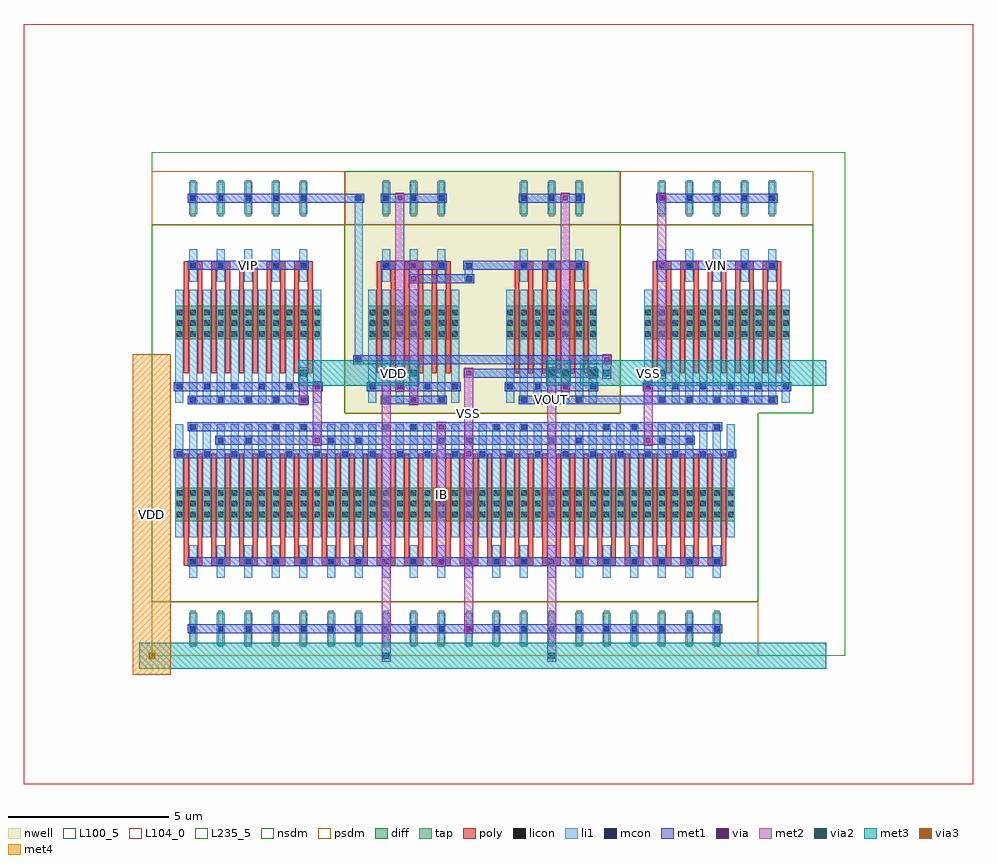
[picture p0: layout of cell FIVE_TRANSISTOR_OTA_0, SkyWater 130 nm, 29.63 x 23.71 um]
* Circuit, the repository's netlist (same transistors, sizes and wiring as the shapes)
* NGSPICE file created from FIVE_TRANSISTOR_OTA_0.ext - technology: sky130A

.subckt PMOS_S_55262173_X3_Y1_1774869087 a_230_462# a_200_252# w_0_0#
X0 w_0_0# a_200_252# a_230_462# w_0_0# sky130_fd_pr__pfet_01v8 ad=0.147 pd=1.33 as=0.147 ps=1.33 w=1.05 l=0.15 M=6
.ends

.subckt SCM_NMOS_33182518_X10_Y1_1774869088 a_200_252# a_402_462# a_147_462#
X0 a_402_462# a_200_252# a_147_462# a_147_462# sky130_fd_pr__nfet_01v8 ad=0.147 pd=1.33 as=0.147 ps=1.33 w=1.05 l=0.15 M=20
X1 a_147_462# a_200_252# a_200_252# a_147_462# sky130_fd_pr__nfet_01v8 ad=0.27825 pd=2.63 as=0.147 ps=1.33 w=1.05 l=0.15 M=20
.ends

.subckt DCL_PMOS_S_56391010_X3_Y1_1774869085 a_200_252# w_0_0#
X0 w_0_0# a_200_252# a_200_252# w_0_0# sky130_fd_pr__pfet_01v8 ad=0.147 pd=1.33 as=0.147 ps=1.33 w=1.05 l=0.15 M=6
.ends

.subckt NMOS_4T_70086367_X5_Y1_1774869086 a_230_462# a_200_252# a_147_462# a_241_1232#
X0 a_230_462# a_200_252# a_147_462# a_241_1232# sky130_fd_pr__nfet_01v8 ad=0.147 pd=1.33 as=0.147 ps=1.33 w=1.05 l=0.15 M=10
.ends

.subckt FIVE_TRANSISTOR_OTA_0 IB VOUT VIP VIN VSS VDD
XPMOS_S_55262173_X3_Y1_1774869087_0 VOUT m1_914_1568# VDD PMOS_S_55262173_X3_Y1_1774869087
XSCM_NMOS_33182518_X10_Y1_1774869088_0 IB m1_3064_1316# VSS SCM_NMOS_33182518_X10_Y1_1774869088
XDCL_PMOS_S_56391010_X3_Y1_1774869085_0 m1_914_1568# VDD DCL_PMOS_S_56391010_X3_Y1_1774869085
XNMOS_4T_70086367_X5_Y1_1774869086_0 VOUT VIN m1_3064_1316# VSS NMOS_4T_70086367_X5_Y1_1774869086
XNMOS_4T_70086367_X5_Y1_1774869086_1 m1_914_1568# VIP m1_3064_1316# VSS NMOS_4T_70086367_X5_Y1_1774869086
.ends

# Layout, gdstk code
from math import pi, radians
import gdstk
lib = gdstk.Library(unit=1e-6, precision=1e-09)
def R(c, l, rs):  # rectangles x0, y0, x1, y1
    for r in rs: c.add(gdstk.rectangle(r[:2], r[2:], *l))
def A(c, l, x, y, w, h, nx, ny, dx, dy):  # array of equal rectangles
    R(c, l, [(x+i*dx, y+j*dy, x+i*dx+w, y+j*dy+h) for i in range(nx) for j in range(ny)])
def P(c, l, *ps):  # polygons
    for p in ps: c.add(gdstk.Polygon(p, *l))
nwell = (64, 20)
diff = (65, 20)
tap = (65, 44)
poly = (66, 20)
licon = (66, 44)
li1 = (67, 20)
mcon = (67, 44)
met1 = (68, 20)
via = (68, 44)
met2 = (69, 20)
via2 = (69, 44)
met3 = (70, 20)
via3 = (70, 44)
met4 = (71, 20)
nsdm = (93, 44)
psdm = (94, 20)
L100_5 = (100, 5)
L104_0 = (104, 0)
L235_5 = (235, 5)

scm_nmos_33182518_x10_y1 = lib.new_cell('SCM_NMOS_33182518_X10_Y1_1774869088')
R(scm_nmos_33182518_x10_y1, diff, [(0.735,2.31,18.185,3.36)])
A(scm_nmos_33182518_x10_y1, tap, 1.205, 6.16, 0.17, 1.12, 20, 1, 0.86, 0)
A(scm_nmos_33182518_x10_y1, poly, 1, 1.26, 0.15, 3.36, 40, 1, 0.43, 0)
A(scm_nmos_33182518_x10_y1, poly, 1, 4.485, 0.58, 0.27, 20, 1, 0.86, 0)
A(scm_nmos_33182518_x10_y1, licon, 0.775, 2.39, 0.17, 0.17, 3, 3, 0.43, 0.34)
A(scm_nmos_33182518_x10_y1, licon, 1.635, 2.39, 0.17, 0.17, 3, 3, 0.43, 0.34)
A(scm_nmos_33182518_x10_y1, licon, 2.495, 2.39, 0.17, 0.17, 3, 3, 0.43, 0.34)
A(scm_nmos_33182518_x10_y1, licon, 3.355, 2.39, 0.17, 0.17, 3, 3, 0.43, 0.34)
A(scm_nmos_33182518_x10_y1, licon, 4.215, 2.39, 0.17, 0.17, 3, 3, 0.43, 0.34)
A(scm_nmos_33182518_x10_y1, licon, 5.075, 2.39, 0.17, 0.17, 3, 3, 0.43, 0.34)
A(scm_nmos_33182518_x10_y1, licon, 5.935, 2.39, 0.17, 0.17, 3, 3, 0.43, 0.34)
A(scm_nmos_33182518_x10_y1, licon, 6.795, 2.39, 0.17, 0.17, 3, 3, 0.43, 0.34)
A(scm_nmos_33182518_x10_y1, licon, 7.655, 2.39, 0.17, 0.17, 3, 3, 0.43, 0.34)
A(scm_nmos_33182518_x10_y1, licon, 8.515, 2.39, 0.17, 0.17, 3, 3, 0.43, 0.34)
A(scm_nmos_33182518_x10_y1, licon, 9.375, 2.39, 0.17, 0.17, 3, 3, 0.43, 0.34)
A(scm_nmos_33182518_x10_y1, licon, 10.235, 2.39, 0.17, 0.17, 3, 3, 0.43, 0.34)
A(scm_nmos_33182518_x10_y1, licon, 11.095, 2.39, 0.17, 0.17, 3, 3, 0.43, 0.34)
A(scm_nmos_33182518_x10_y1, licon, 11.955, 2.39, 0.17, 0.17, 3, 3, 0.43, 0.34)
A(scm_nmos_33182518_x10_y1, licon, 12.815, 2.39, 0.17, 0.17, 3, 3, 0.43, 0.34)
A(scm_nmos_33182518_x10_y1, licon, 13.675, 2.39, 0.17, 0.17, 3, 3, 0.43, 0.34)
A(scm_nmos_33182518_x10_y1, licon, 14.535, 2.39, 0.17, 0.17, 3, 3, 0.43, 0.34)
A(scm_nmos_33182518_x10_y1, licon, 15.395, 2.39, 0.17, 0.17, 3, 3, 0.43, 0.34)
A(scm_nmos_33182518_x10_y1, licon, 16.255, 2.39, 0.17, 0.17, 3, 3, 0.43, 0.34)
A(scm_nmos_33182518_x10_y1, licon, 17.115, 2.39, 0.17, 0.17, 3, 3, 0.43, 0.34)
A(scm_nmos_33182518_x10_y1, licon, 1.205, 4.535, 0.17, 0.17, 20, 2, 0.86, 2.1)
A(scm_nmos_33182518_x10_y1, li1, 0.735, 0.335, 0.25, 3.53, 41, 1, 0.43, 0)
A(scm_nmos_33182518_x10_y1, li1, 1.165, 4.115, 0.25, 1.01, 20, 2, 0.86, 2.1)
A(scm_nmos_33182518_x10_y1, mcon, 0.775, 1.175, 0.17, 0.17, 21, 1, 0.86, 0)
A(scm_nmos_33182518_x10_y1, mcon, 1.205, 4.535, 0.17, 0.17, 20, 2, 0.86, 2.1)
R(scm_nmos_33182518_x10_y1, mcon, [(1.205,0.335,1.375,0.505), (3.785,0.335,3.955,0.505), (4.645,0.335,4.815,0.505), (7.225,0.335,7.395,0.505), (8.085,0.335,8.255,0.505), (10.665,0.335,10.835,0.505), (11.525,0.335,11.695,0.505), (14.105,0.335,14.275,0.505), (14.965,0.335,15.135,0.505), (17.545,0.335,17.715,0.505), (2.065,0.755,2.235,0.925), (2.925,0.755,3.095,0.925), (5.505,0.755,5.675,0.925), (6.365,0.755,6.535,0.925), (8.945,0.755,9.115,0.925), (9.805,0.755,9.975,0.925), (12.385,0.755,12.555,0.925), (13.245,0.755,13.415,0.925), (15.825,0.755,15.995,0.925), (16.685,0.755,16.855,0.925)])
R(scm_nmos_33182518_x10_y1, met1, [(1.12,0.28,17.8,0.56), (1.98,0.7,16.94,0.98), (0.69,1.12,18.23,1.4), (1.12,4.48,17.8,4.76), (1.12,6.58,17.8,6.86)])
R(scm_nmos_33182518_x10_y1, via, [(8.955,0.345,9.105,0.495), (9.815,1.185,9.965,1.335), (8.955,4.545,9.105,4.695), (9.815,6.645,9.965,6.795)])
R(scm_nmos_33182518_x10_y1, met2, [(8.89,0.26,9.17,4.78), (9.75,1.1,10.03,6.88)])
R(scm_nmos_33182518_x10_y1, nsdm, [(0,0,18.92,5.88)])
R(scm_nmos_33182518_x10_y1, psdm, [(0,5.88,18.92,7.56)])
R(scm_nmos_33182518_x10_y1, L100_5, [(0,0,18.92,7.56)])

dcl_pmos_s_56391010_x3_y = lib.new_cell('DCL_PMOS_S_56391010_X3_Y1_1774869085')
R(dcl_pmos_s_56391010_x3_y, nwell, [(0,0,4.3,7.56)])
R(dcl_pmos_s_56391010_x3_y, diff, [(0.735,2.31,3.565,3.36)])
A(dcl_pmos_s_56391010_x3_y, tap, 1.205, 6.16, 0.17, 1.12, 3, 1, 0.86, 0)
A(dcl_pmos_s_56391010_x3_y, poly, 1, 1.26, 0.15, 3.36, 6, 1, 0.43, 0)
A(dcl_pmos_s_56391010_x3_y, poly, 1, 4.485, 0.58, 0.27, 3, 1, 0.86, 0)
A(dcl_pmos_s_56391010_x3_y, licon, 0.775, 2.39, 0.17, 0.17, 3, 3, 0.43, 0.34)
A(dcl_pmos_s_56391010_x3_y, licon, 1.635, 2.39, 0.17, 0.17, 3, 3, 0.43, 0.34)
A(dcl_pmos_s_56391010_x3_y, licon, 2.495, 2.39, 0.17, 0.17, 3, 3, 0.43, 0.34)
A(dcl_pmos_s_56391010_x3_y, licon, 1.205, 4.535, 0.17, 0.17, 3, 2, 0.86, 2.1)
A(dcl_pmos_s_56391010_x3_y, li1, 0.735, 0.335, 0.25, 3.53, 7, 1, 0.43, 0)
A(dcl_pmos_s_56391010_x3_y, li1, 1.165, 4.115, 0.25, 1.01, 3, 2, 0.86, 2.1)
A(dcl_pmos_s_56391010_x3_y, mcon, 1.205, 0.335, 0.17, 0.17, 3, 2, 0.86, 4.2)
A(dcl_pmos_s_56391010_x3_y, mcon, 0.775, 0.755, 0.17, 0.17, 4, 1, 0.86, 0)
A(dcl_pmos_s_56391010_x3_y, mcon, 1.205, 6.635, 0.17, 0.17, 3, 1, 0.86, 0)
R(dcl_pmos_s_56391010_x3_y, met1, [(1.12,0.28,3.18,0.56), (0.69,0.7,3.61,0.98), (1.12,4.48,3.18,4.76), (1.12,6.58,3.18,6.86)])
R(dcl_pmos_s_56391010_x3_y, via, [(2.075,0.345,2.225,0.495), (2.505,0.765,2.655,0.915), (2.075,4.545,2.225,4.695), (2.505,6.645,2.655,6.795)])
R(dcl_pmos_s_56391010_x3_y, met2, [(2.01,0.26,2.29,4.78), (2.44,0.68,2.72,6.88)])
R(dcl_pmos_s_56391010_x3_y, nsdm, [(0,5.88,4.3,7.56)])
R(dcl_pmos_s_56391010_x3_y, psdm, [(0,0,4.3,5.88)])
R(dcl_pmos_s_56391010_x3_y, L100_5, [(0,0,4.3,7.56)])

pmos_s_55262173_x3_y1_17 = lib.new_cell('PMOS_S_55262173_X3_Y1_1774869087')
R(pmos_s_55262173_x3_y1_17, nwell, [(0,0,4.3,7.56)])
R(pmos_s_55262173_x3_y1_17, diff, [(0.735,2.31,3.565,3.36)])
A(pmos_s_55262173_x3_y1_17, tap, 1.205, 6.16, 0.17, 1.12, 3, 1, 0.86, 0)
A(pmos_s_55262173_x3_y1_17, poly, 1, 1.26, 0.15, 3.36, 6, 1, 0.43, 0)
A(pmos_s_55262173_x3_y1_17, poly, 1, 4.485, 0.58, 0.27, 3, 1, 0.86, 0)
A(pmos_s_55262173_x3_y1_17, licon, 0.775, 2.39, 0.17, 0.17, 3, 3, 0.43, 0.34)
A(pmos_s_55262173_x3_y1_17, licon, 1.635, 2.39, 0.17, 0.17, 3, 3, 0.43, 0.34)
A(pmos_s_55262173_x3_y1_17, licon, 2.495, 2.39, 0.17, 0.17, 3, 3, 0.43, 0.34)
A(pmos_s_55262173_x3_y1_17, licon, 1.205, 4.535, 0.17, 0.17, 3, 2, 0.86, 2.1)
A(pmos_s_55262173_x3_y1_17, li1, 0.735, 0.335, 0.25, 3.53, 7, 1, 0.43, 0)
A(pmos_s_55262173_x3_y1_17, li1, 1.165, 4.115, 0.25, 1.01, 3, 2, 0.86, 2.1)
A(pmos_s_55262173_x3_y1_17, mcon, 1.205, 0.335, 0.17, 0.17, 3, 2, 0.86, 4.2)
A(pmos_s_55262173_x3_y1_17, mcon, 0.775, 0.755, 0.17, 0.17, 4, 1, 0.86, 0)
A(pmos_s_55262173_x3_y1_17, mcon, 1.205, 6.635, 0.17, 0.17, 3, 1, 0.86, 0)
R(pmos_s_55262173_x3_y1_17, met1, [(1.12,0.28,3.18,0.56), (0.69,0.7,3.61,0.98), (1.12,4.48,3.18,4.76), (1.12,6.58,3.18,6.86)])
R(pmos_s_55262173_x3_y1_17, via, [(2.505,0.765,2.655,0.915), (2.505,6.645,2.655,6.795)])
R(pmos_s_55262173_x3_y1_17, met2, [(2.44,0.68,2.72,6.88)])
R(pmos_s_55262173_x3_y1_17, nsdm, [(0,5.88,4.3,7.56)])
R(pmos_s_55262173_x3_y1_17, psdm, [(0,0,4.3,5.88)])
R(pmos_s_55262173_x3_y1_17, L100_5, [(0,0,4.3,7.56)])

nmos_4t_70086367_x5_y1_1 = lib.new_cell('NMOS_4T_70086367_X5_Y1_1774869086')
R(nmos_4t_70086367_x5_y1_1, diff, [(0.735,2.31,5.285,3.36)])
A(nmos_4t_70086367_x5_y1_1, tap, 1.205, 6.16, 0.17, 1.12, 5, 1, 0.86, 0)
A(nmos_4t_70086367_x5_y1_1, poly, 1, 1.26, 0.15, 3.36, 10, 1, 0.43, 0)
A(nmos_4t_70086367_x5_y1_1, poly, 1, 4.485, 0.58, 0.27, 5, 1, 0.86, 0)
A(nmos_4t_70086367_x5_y1_1, licon, 0.775, 2.39, 0.17, 0.17, 3, 3, 0.43, 0.34)
A(nmos_4t_70086367_x5_y1_1, licon, 1.635, 2.39, 0.17, 0.17, 3, 3, 0.43, 0.34)
A(nmos_4t_70086367_x5_y1_1, licon, 2.495, 2.39, 0.17, 0.17, 3, 3, 0.43, 0.34)
A(nmos_4t_70086367_x5_y1_1, licon, 3.355, 2.39, 0.17, 0.17, 3, 3, 0.43, 0.34)
A(nmos_4t_70086367_x5_y1_1, licon, 4.215, 2.39, 0.17, 0.17, 3, 3, 0.43, 0.34)
A(nmos_4t_70086367_x5_y1_1, licon, 1.205, 4.535, 0.17, 0.17, 5, 2, 0.86, 2.1)
A(nmos_4t_70086367_x5_y1_1, li1, 0.735, 0.335, 0.25, 3.53, 11, 1, 0.43, 0)
A(nmos_4t_70086367_x5_y1_1, li1, 1.165, 4.115, 0.25, 1.01, 5, 2, 0.86, 2.1)
A(nmos_4t_70086367_x5_y1_1, mcon, 1.205, 0.335, 0.17, 0.17, 5, 2, 0.86, 4.2)
A(nmos_4t_70086367_x5_y1_1, mcon, 0.775, 0.755, 0.17, 0.17, 6, 1, 0.86, 0)
A(nmos_4t_70086367_x5_y1_1, mcon, 1.205, 6.635, 0.17, 0.17, 5, 1, 0.86, 0)
R(nmos_4t_70086367_x5_y1_1, met1, [(1.12,0.28,4.9,0.56), (0.69,0.7,5.33,0.98), (1.12,4.48,4.9,4.76), (1.12,6.58,4.9,6.86)])
R(nmos_4t_70086367_x5_y1_1, nsdm, [(0,0,6.02,5.88)])
R(nmos_4t_70086367_x5_y1_1, psdm, [(0,5.88,6.02,7.56)])
R(nmos_4t_70086367_x5_y1_1, L100_5, [(0,0,6.02,7.56)])

five_transistor_ota_0 = lib.new_cell('FIVE_TRANSISTOR_OTA_0')
R(five_transistor_ota_0, li1, [(6.325,9.155,6.575,9.325), (6.325,9.155,6.575,9.325), (6.325,9.155,6.575,9.325), (6.325,9.24,6.575,14.28), (9.765,11.675,10.015,11.845), (9.765,11.675,10.015,11.845), (9.765,11.76,10.015,12.18), (9.765,12.095,10.015,12.265), (9.765,12.095,10.015,12.265), (6.325,14.195,6.575,14.365), (6.325,14.195,6.575,14.365), (6.325,14.195,6.575,14.365)])
R(five_transistor_ota_0, mcon, [(6.365,9.155,6.535,9.325), (6.365,9.155,6.535,9.325), (6.365,9.155,6.535,9.325), (9.805,11.675,9.975,11.845), (9.805,11.675,9.975,11.845), (9.805,12.095,9.975,12.265), (9.805,12.095,9.975,12.265), (6.365,14.195,6.535,14.365), (6.365,14.195,6.535,14.365), (6.365,14.195,6.535,14.365)])
R(five_transistor_ota_0, met1, [(5,6.58,5.32,6.86), (5,6.58,5.32,6.86), (5,6.58,5.32,6.86), (5,6.58,5.32,6.86), (15.32,6.58,15.64,6.86), (15.32,6.58,15.64,6.86), (4.57,7.84,4.89,8.12), (4.57,7.84,4.89,8.12), (4.57,7.84,4.89,8.12), (4.57,7.84,4.89,8.12), (13.33,7.84,15.91,8.12), (5,8.26,5.32,8.54), (5,8.26,5.32,8.54), (5,8.26,5.32,8.54), (5,8.26,5.32,8.54), (15.32,8.26,15.64,8.54), (15.32,8.26,15.64,8.54), (7.15,8.68,7.47,8.96), (7.15,8.68,7.47,8.96), (7.15,8.68,7.47,8.96), (7.31,8.68,7.74,8.96), (7.58,8.68,7.9,8.96), (7.58,8.68,7.9,8.96), (7.58,8.68,7.9,8.96), (9.73,8.68,10.05,8.96), (9.73,8.68,10.05,8.96), (9.73,8.68,10.05,8.96), (9.73,8.68,10.05,8.96), (9.89,8.68,13.76,8.96), (13.6,8.68,13.92,8.96), (6.28,9.1,6.62,9.38), (6.28,9.1,6.62,9.38), (6.28,9.1,6.62,9.38), (6.45,9.1,14.19,9.38), (14.03,9.1,14.35,9.38), (14.03,9.1,14.35,9.38), (14.03,9.1,14.35,9.38), (8.01,11.62,8.33,11.9), (8.01,11.62,8.33,11.9), (8.17,11.62,9.89,11.9), (9.72,11.62,10.06,11.9), (9.72,11.62,10.06,11.9), (9.72,12.04,10.06,12.32), (9.72,12.04,10.06,12.32), (9.89,12.04,11.61,12.32), (4.73,14.14,6.45,14.42), (6.28,14.14,6.62,14.42), (6.28,14.14,6.62,14.42), (6.28,14.14,6.62,14.42), (15.75,14.14,16.07,14.42), (15.75,14.14,16.07,14.42)])
P(five_transistor_ota_0, met1, [(0,0),(0,0),(0,0),(0,0)],
  [(0,0),(0,0),(0,0),(0,0)],
  [(0,0),(0,0),(0,0),(0,0)],
  [(0,0),(0,0),(0,0),(0,0)],
  [(0,0),(0,0),(0,0),(0,0)],
  [(0,0),(0,0),(0,0),(0,0)],
  [(0,0),(0,0),(0,0),(0,0)],
  [(0,0),(0,0),(0,0),(0,0)],
  [(0,0),(0,0),(0,0),(0,0)],
  [(0,0),(0,0),(0,0),(0,0)],
  [(0,0),(0,0),(0,0),(0,0)],
  [(0,0),(0,0),(0,0),(0,0)],
  [(0,0),(0,0),(0,0),(0,0)],
  [(0,0),(0,0),(0,0),(0,0)])
R(five_transistor_ota_0, via, [(5.085,6.645,5.235,6.795), (5.085,6.645,5.235,6.795), (5.085,6.645,5.235,6.795), (5.085,6.645,5.235,6.795), (15.405,6.645,15.555,6.795), (15.405,6.645,15.555,6.795), (4.655,7.905,4.805,8.055), (4.655,7.905,4.805,8.055), (4.655,7.905,4.805,8.055), (4.655,7.905,4.805,8.055), (5.085,8.325,5.235,8.475), (5.085,8.325,5.235,8.475), (5.085,8.325,5.235,8.475), (5.085,8.325,5.235,8.475), (15.405,8.325,15.555,8.475), (15.405,8.325,15.555,8.475), (7.235,8.745,7.385,8.895), (7.235,8.745,7.385,8.895), (7.235,8.745,7.385,8.895), (7.665,8.745,7.815,8.895), (7.665,8.745,7.815,8.895), (7.665,8.745,7.815,8.895), (9.815,8.745,9.965,8.895), (9.815,8.745,9.965,8.895), (9.815,8.745,9.965,8.895), (9.815,8.745,9.965,8.895), (13.685,8.745,13.835,8.895), (14.115,9.165,14.265,9.315), (14.115,9.165,14.265,9.315), (14.115,9.165,14.265,9.315), (8.095,11.685,8.245,11.835), (8.095,11.685,8.245,11.835), (15.835,14.205,15.985,14.355), (15.835,14.205,15.985,14.355)])
R(five_transistor_ota_0, met2, [(7.17,-0.185,7.45,0.185), (7.17,-0.185,7.45,0.185), (7.17,-0.185,7.45,0.185), (12.33,-0.185,12.61,0.185), (12.33,-0.185,12.61,0.185), (7.17,0,7.45,8.82), (12.33,0,12.61,8.82), (9.75,6.3,10.03,8.82), (5.02,6.56,5.3,6.88), (5.02,6.56,5.3,6.88), (5.02,6.56,5.3,6.88), (5.02,6.56,5.3,6.88), (15.34,6.56,15.62,6.88), (15.34,6.56,15.62,6.88), (5.02,6.72,5.3,8.4), (15.34,6.72,15.62,8.4), (4.59,7.82,4.87,8.14), (4.59,7.82,4.87,8.14), (4.59,7.82,4.87,8.14), (4.59,7.82,4.87,8.14), (4.59,7.98,4.87,8.82), (5.02,8.24,5.3,8.56), (5.02,8.24,5.3,8.56), (5.02,8.24,5.3,8.56), (5.02,8.24,5.3,8.56), (15.34,8.24,15.62,8.56), (15.34,8.24,15.62,8.56), (4.59,8.635,4.87,9.005), (4.59,8.635,4.87,9.005), (4.59,8.635,4.87,9.005), (4.59,8.635,4.87,9.005), (8.03,8.635,8.31,9.005), (8.03,8.635,8.31,9.005), (8.03,8.635,8.31,9.005), (8.03,8.635,8.31,9.005), (12.33,8.635,12.61,9.005), (12.33,8.635,12.61,9.005), (12.76,8.635,13.04,9.005), (12.76,8.635,13.04,9.005), (13.62,8.635,13.9,9.005), (14.05,8.635,14.33,9.005), (14.05,8.635,14.33,9.005), (14.05,8.635,14.33,9.005), (15.77,8.635,16.05,9.005), (15.77,8.635,16.05,9.005), (7.17,8.66,7.45,8.98), (7.17,8.66,7.45,8.98), (7.17,8.66,7.45,8.98), (7.6,8.66,7.88,8.98), (7.6,8.66,7.88,8.98), (7.6,8.66,7.88,8.98), (9.75,8.66,10.03,8.98), (9.75,8.66,10.03,8.98), (9.75,8.66,10.03,8.98), (9.75,8.66,10.03,8.98), (13.62,8.66,13.9,8.98), (13.62,8.699,13.9,8.941), (14.05,8.82,14.33,9.24), (15.77,8.82,16.05,14.28), (14.05,9.08,14.33,9.4), (14.05,9.08,14.33,9.4), (14.05,9.08,14.33,9.4), (8.03,11.6,8.31,11.92), (8.03,11.6,8.31,11.92), (15.77,14.12,16.05,14.44), (15.77,14.12,16.05,14.44)])
P(five_transistor_ota_0, met2, [(0,0),(0,0),(0,0),(0,0)],
  [(0,0),(0,0),(0,0),(0,0)],
  [(0,0),(0,0),(0,0),(0,0)],
  [(0,0),(0,0),(0,0),(0,0)],
  [(0,0),(0,0),(0,0),(0,0)],
  [(0,0),(0,0),(0,0),(0,0)])
R(five_transistor_ota_0, via2, [(7.21,-0.1,7.41,0.1), (7.21,-0.1,7.41,0.1), (7.21,-0.1,7.41,0.1), (12.37,-0.1,12.57,0.1), (12.37,-0.1,12.57,0.1), (4.63,8.72,4.83,8.92), (4.63,8.72,4.83,8.92), (4.63,8.72,4.83,8.92), (4.63,8.72,4.83,8.92), (8.07,8.72,8.27,8.92), (8.07,8.72,8.27,8.92), (8.07,8.72,8.27,8.92), (8.07,8.72,8.27,8.92), (12.37,8.72,12.57,8.92), (12.37,8.72,12.57,8.92), (12.8,8.72,13,8.92), (12.8,8.72,13,8.92), (13.66,8.72,13.86,8.92), (14.09,8.72,14.29,8.92), (14.09,8.72,14.29,8.92), (14.09,8.72,14.29,8.92), (15.81,8.72,16.01,8.92), (15.81,8.72,16.01,8.92)])
A(five_transistor_ota_0, met3, -0.4, -0.4, 4.24, 0.8, 3, 1, 3.44, 0)
R(five_transistor_ota_0, met3, [(-0.165,-0.4,0.165,0.4), (7.145,-0.4,7.475,0.4), (7.145,-0.4,7.475,0.4), (7.145,-0.4,7.475,0.4), (9.92,-0.4,12.24,0.4), (11.44,-0.4,14.16,0.4), (12.305,-0.4,12.635,0.4), (12.305,-0.4,12.635,0.4), (13.36,-0.4,17.6,0.4), (16.8,-0.4,21.04,0.4), (4.565,8.42,4.895,9.22), (4.565,8.42,4.895,9.22), (4.565,8.42,4.895,9.22), (4.565,8.42,4.895,9.22), (4.73,8.42,8.17,9.22), (8.005,8.42,8.335,9.22), (8.005,8.42,8.335,9.22), (8.005,8.42,8.335,9.22), (8.005,8.42,8.335,9.22), (12.305,8.42,12.635,9.22), (12.305,8.42,12.635,9.22), (12.47,8.42,12.9,9.22), (12.735,8.42,13.065,9.22), (12.735,8.42,13.065,9.22), (13.36,8.42,17.6,9.22), (13.595,8.42,13.925,9.22), (14.025,8.42,14.355,9.22), (14.025,8.42,14.355,9.22), (14.025,8.42,14.355,9.22), (15.745,8.42,16.075,9.22), (15.745,8.42,16.075,9.22), (16.8,8.42,21.04,9.22)])
R(five_transistor_ota_0, via3, [(-0.1,-0.1,0.1,0.1)])
R(five_transistor_ota_0, met4, [(-0.59,-0.59,0.59,9.41), (-0.59,-0.165,0.59,0.165)])
R(five_transistor_ota_0, L104_0, [(-4,-4,25.63,19.71)])
R(five_transistor_ota_0, L235_5, [(0,0,21.63,15.71)])
five_transistor_ota_0.add(gdstk.Reference(scm_nmos_33182518_x10_y1, (0,7.56), x_reflection=True))
five_transistor_ota_0.add(gdstk.Reference(dcl_pmos_s_56391010_x3_y, (10.32,7.56), rotation=pi, x_reflection=True))
five_transistor_ota_0.add(gdstk.Reference(pmos_s_55262173_x3_y1_17, (10.32,7.56)))
five_transistor_ota_0.add(gdstk.Reference(nmos_4t_70086367_x5_y1_1, (0,7.56)))
five_transistor_ota_0.add(gdstk.Reference(nmos_4t_70086367_x5_y1_1, (20.64,7.56), rotation=pi, x_reflection=True))
five_transistor_ota_0.add(gdstk.Label('IB', (9.03,5.04), layer=69, texttype=5))
five_transistor_ota_0.add(gdstk.Label('VOUT', (12.47,7.98), layer=68, texttype=5))
five_transistor_ota_0.add(gdstk.Label('VIP', (3.01,12.18), layer=68, texttype=5))
five_transistor_ota_0.add(gdstk.Label('VIN', (17.63,12.18), layer=68, texttype=5))
five_transistor_ota_0.add(gdstk.Label('VSS', (9.89,7.56), layer=69, texttype=5))
five_transistor_ota_0.add(gdstk.Label('VSS', (15.48,8.82), layer=70, texttype=5))
five_transistor_ota_0.add(gdstk.Label('VSS', (15.48,8.82), layer=70, texttype=5))
five_transistor_ota_0.add(gdstk.Label('VSS', (15.48,8.82), layer=70, texttype=5))
five_transistor_ota_0.add(gdstk.Label('VSS', (15.48,8.82), layer=70, texttype=5))
five_transistor_ota_0.add(gdstk.Label('VSS', (15.48,8.82), layer=70, texttype=5))
five_transistor_ota_0.add(gdstk.Label('VSS', (15.48,8.82), layer=70, texttype=5))
five_transistor_ota_0.add(gdstk.Label('VSS', (15.48,8.82), layer=70, texttype=5))
five_transistor_ota_0.add(gdstk.Label('VSS', (15.48,8.82), layer=70, texttype=5))
five_transistor_ota_0.add(gdstk.Label('VSS', (15.48,8.82), layer=70, texttype=5))
five_transistor_ota_0.add(gdstk.Label('VSS', (15.48,8.82), layer=70, texttype=5))
five_transistor_ota_0.add(gdstk.Label('VSS', (15.48,8.82), layer=70, texttype=5))
five_transistor_ota_0.add(gdstk.Label('VSS', (15.48,8.82), layer=70, texttype=5))
five_transistor_ota_0.add(gdstk.Label('VDD', (0,4.41), layer=71, texttype=5))
five_transistor_ota_0.add(gdstk.Label('VDD', (7.525,8.82), layer=68, texttype=5))
five_transistor_ota_0.add(gdstk.Label('VDD', (0,4.41), layer=71, texttype=5))
five_transistor_ota_0.add(gdstk.Label('VDD', (0,4.41), layer=71, texttype=5))
five_transistor_ota_0.add(gdstk.Label('VDD', (0,4.41), layer=71, texttype=5))
five_transistor_ota_0.add(gdstk.Label('VDD', (0,4.41), layer=71, texttype=5))
five_transistor_ota_0.add(gdstk.Label('VDD', (0,4.41), layer=71, texttype=5))
five_transistor_ota_0.add(gdstk.Label('VDD', (0,4.41), layer=71, texttype=5))
five_transistor_ota_0.add(gdstk.Label('VDD', (0,4.41), layer=71, texttype=5))

lib.write_gds('FIVE_TRANSISTOR_OTA_0.gds')
